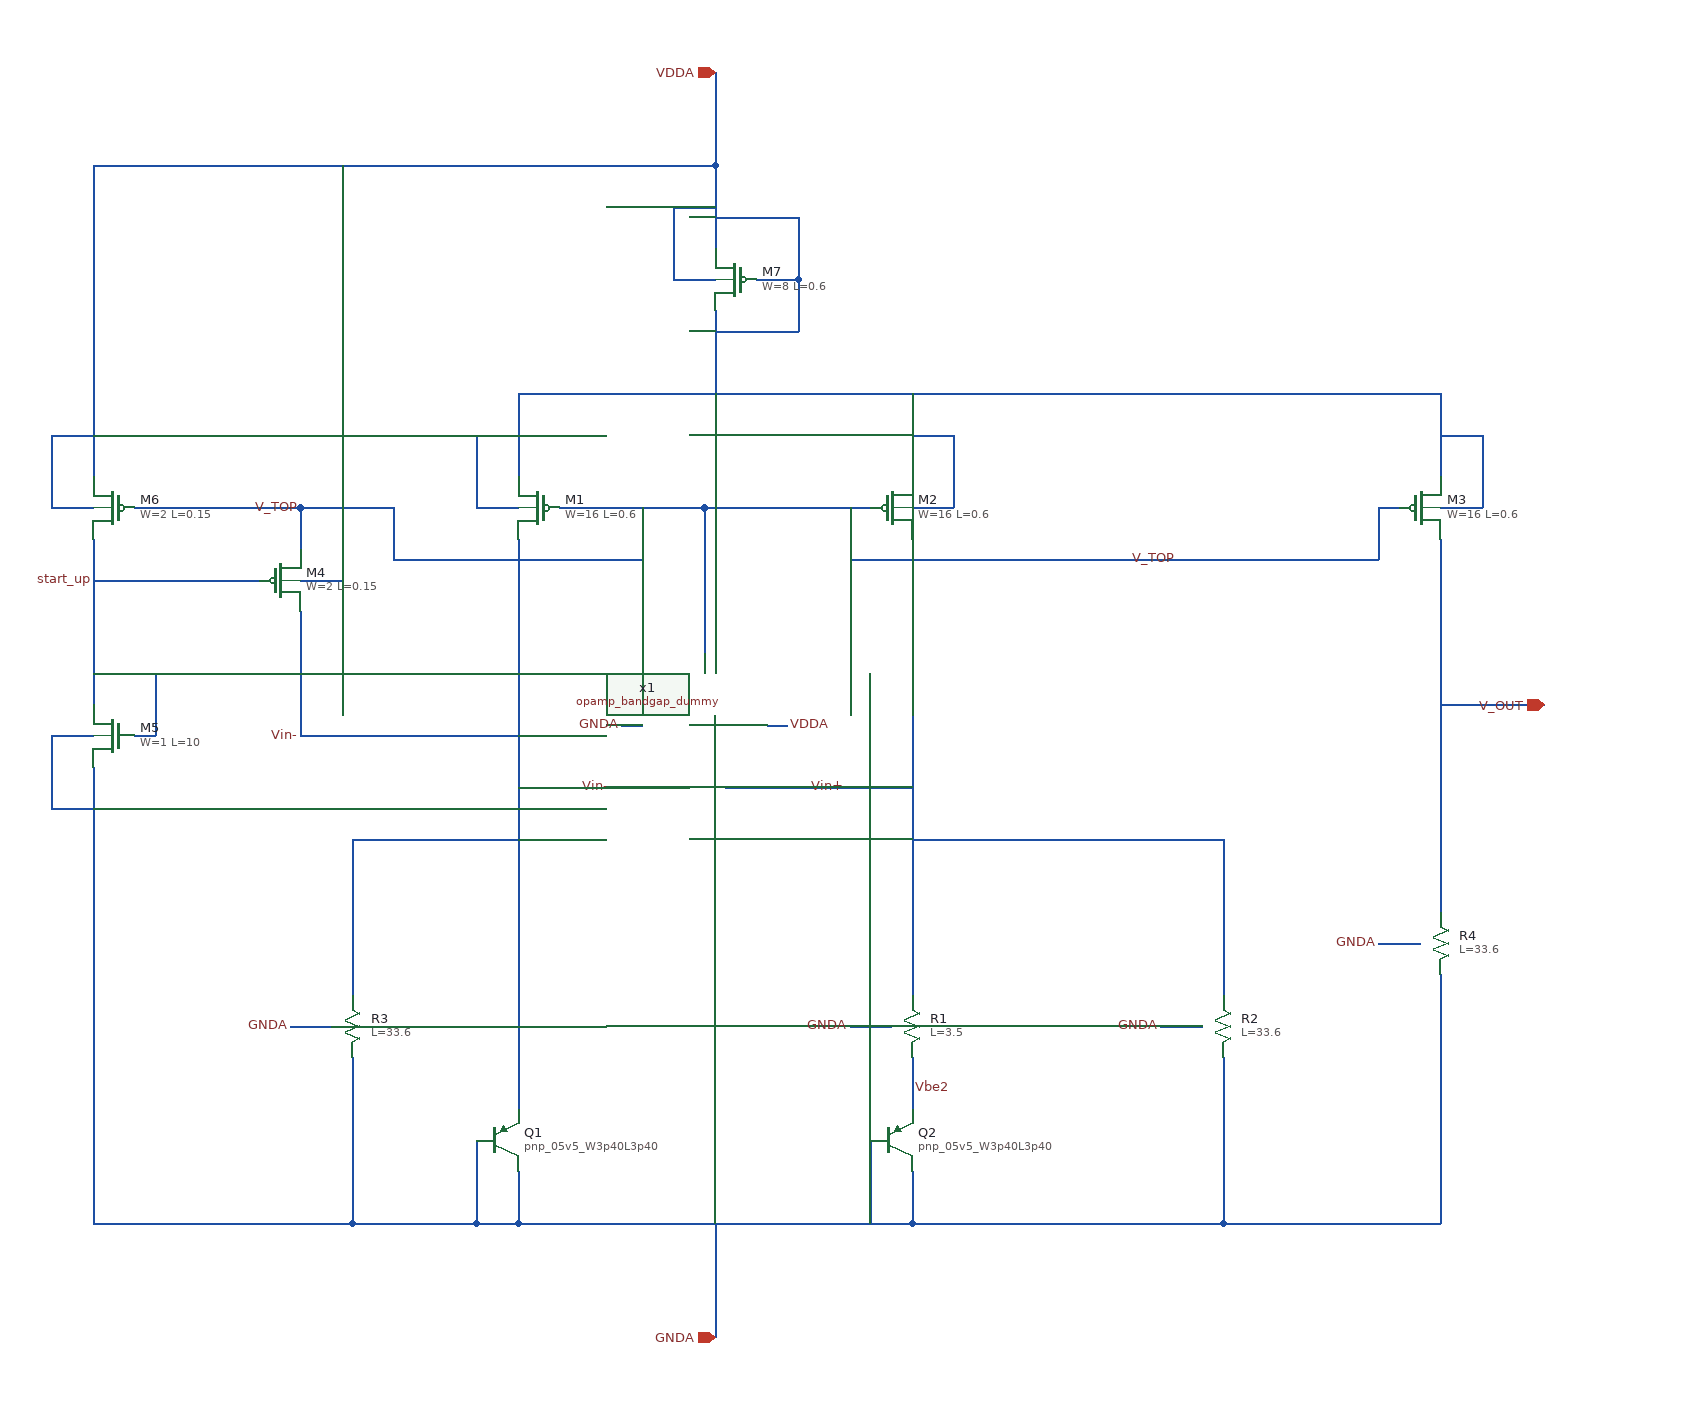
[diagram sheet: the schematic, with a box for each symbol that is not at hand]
v {xschem version=3.4.6 file_version=1.2}
G {}
K {}
V {}
S {}
E {}
N 700 -260 1080 -260 {
lab=GNDA}
N 660 -340 660 -260 {
lab=GNDA}
N 1040 -340 1040 -260 {
lab=GNDA}
N 660 -260 700 -260 {
lab=GNDA}
N 740 -950 880 -950 {
lab=V_TOP}
N 880 -950 1040 -950 {
lab=V_TOP}
N 700 -1060 700 -980 {
lab=VDDA}
N 1080 -1060 1080 -980 {
lab=VDDA}
N 540 -630 700 -630 {
lab=Vin-}
N 1080 -420 1080 -370 {lab=Vbe2}
N 1380 -420 1380 -260 {lab=GNDA}
N 540 -420 540 -260 {lab=GNDA}
N 1080 -630 1380 -630 {lab=Vin+}
N 1080 -260 1380 -260 {lab=GNDA}
N 1590 -500 1590 -260 {lab=GNDA}
N 1380 -260 1590 -260 {lab=GNDA}
N 1080 -950 1120 -950 {lab=VDDA}
N 1120 -1020 1120 -950 {lab=VDDA}
N 1080 -1020 1120 -1020 {lab=VDDA}
N 660 -950 700 -950 {lab=VDDA}
N 660 -1020 660 -950 {lab=VDDA}
N 660 -1020 700 -1020 {lab=VDDA}
N 1590 -1060 1590 -980 {
lab=VDDA}
N 1590 -950 1630 -950 {lab=VDDA}
N 1630 -1020 1630 -950 {lab=VDDA}
N 1590 -1020 1630 -1020 {lab=VDDA}
N 1020 -950 1020 -900 {lab=V_TOP}
N 1020 -900 1530 -900 {lab=V_TOP}
N 1530 -950 1530 -900 {lab=V_TOP}
N 1530 -950 1550 -950 {lab=V_TOP}
N 1590 -760 1690 -760 {lab=V_OUT}
N 900 -680 1080 -680 {lab=Vin+}
N 700 -680 860 -680 {lab=Vin-}
N 540 -260 660 -260 {lab=GNDA}
N 1080 -310 1080 -260 {lab=GNDA}
N 700 -310 700 -260 {lab=GNDA}
N 490 -950 490 -910 {lab=V_TOP}
N 290 -850 290 -760 {lab=start_up}
N 290 -1060 290 -980 {
lab=VDDA}
N 250 -950 290 -950 {lab=VDDA}
N 250 -1020 250 -950 {lab=VDDA}
N 250 -1020 290 -1020 {lab=VDDA}
N 290 -920 290 -850 {lab=start_up}
N 490 -950 580 -950 {lab=V_TOP}
N 580 -950 580 -900 {lab=V_TOP}
N 580 -900 820 -900 {lab=V_TOP}
N 290 -880 450 -880 {lab=start_up}
N 290 -260 540 -260 {lab=GNDA}
N 880 -950 880 -810 {lab=V_TOP}
N 820 -950 820 -900 {lab=V_TOP}
N 490 -730 700 -730 {lab=Vin-}
N 250 -660 290 -660 {lab=GNDA}
N 250 -730 250 -660 {lab=GNDA}
N 250 -730 290 -730 {lab=GNDA}
N 290 -700 290 -630 {lab=GNDA}
N 290 -340 290 -260 {lab=GNDA}
N 490 -880 530 -880 {lab=VDDA}
N 530 -930 530 -880 {lab=VDDA}
N 290 -630 290 -340 {lab=GNDA}
N 330 -950 490 -950 {lab=V_TOP}
N 290 -790 350 -790 {lab=start_up}
N 350 -790 350 -730 {lab=start_up}
N 330 -730 350 -730 {lab=start_up}
N 490 -850 490 -730 {lab=Vin-}
N 700 -920 700 -370 {lab=Vin-}
N 540 -630 540 -480 {lab=Vin-}
N 1080 -920 1080 -480 {lab=Vin+}
N 1380 -630 1380 -480 {lab=Vin+}
N 1590 -920 1590 -560 {lab=V_OUT}
N 890 -1370 890 -1280 {lab=VDDA}
N 890 -260 890 -150 {lab=GNDA}
N 480 -450 520 -450 {lab=GNDA}
N 1020 -450 1060 -450 {lab=GNDA}
N 1320 -450 1360 -450 {lab=GNDA}
N 1530 -530 1570 -530 {lab=GNDA}
N 800 -740 820 -740 {lab=GNDA}
N 940 -740 960 -740 {lab=VDDA}
N 890 -1280 890 -1200 {
lab=VDDA}
N 850 -1170 890 -1170 {lab=VDDA}
N 850 -1240 850 -1170 {lab=VDDA}
N 850 -1240 890 -1240 {lab=VDDA}
N 290 -1280 290 -1060 {lab=VDDA}
N 700 -1060 1590 -1060 {lab=VDDA}
N 930 -1170 970 -1170 {lab=VDDA}
N 970 -1230 970 -1170 {lab=VDDA}
N 890 -1230 970 -1230 {lab=VDDA}
N 890 -1140 890 -1060 {lab=VDDA}
N 290 -1280 890 -1280 {lab=VDDA}
N 530 -1280 530 -930 {lab=VDDA}
N 970 -1170 970 -1120 {lab=VDDA}
N 890 -1120 970 -1120 {lab=VDDA}
C {devices/lab_pin.sym} 1080 -390 2 0 {name=p5 sig_type=std_logic lab=Vbe2}
C {devices/lab_pin.sym} 960 -740 2 0 {name=p4 sig_type=std_logic lab=VDDA
}
C {sky130_fd_pr/pnp_05v5.sym} 680 -340 0 0 {name=Q1
model=pnp_05v5_W3p40L3p40
m=1
spiceprefix=X
}
C {sky130_fd_pr/pnp_05v5.sym} 1060 -340 0 0 {name=Q2
model=pnp_05v5_W3p40L3p40
m=6
spiceprefix=X
}
C {sky130_fd_pr/pfet_01v8.sym} 720 -950 0 1 {name=M1
W=16
L=0.6
nf=4
mult=1
ad="'int((nf+1)/2) * W/nf * 0.29'" 
pd="'2*int((nf+1)/2) * (W/nf + 0.29)'"
as="'int((nf+2)/2) * W/nf * 0.29'" 
ps="'2*int((nf+2)/2) * (W/nf + 0.29)'"
nrd="'0.29 / W'" nrs="'0.29 / W'"
sa=0 sb=0 sd=0
model=pfet_01v8
spiceprefix=X
}
C {sky130_fd_pr/pfet_01v8.sym} 1060 -950 0 0 {name=M2
W=16
L=0.6
nf=4
mult=1
ad="'int((nf+1)/2) * W/nf * 0.29'" 
pd="'2*int((nf+1)/2) * (W/nf + 0.29)'"
as="'int((nf+2)/2) * W/nf * 0.29'" 
ps="'2*int((nf+2)/2) * (W/nf + 0.29)'"
nrd="'0.29 / W'" nrs="'0.29 / W'"
sa=0 sb=0 sd=0
model=pfet_01v8
spiceprefix=X
}
C {sky130_fd_pr/pfet_01v8.sym} 1570 -950 0 0 {name=M3
W=16
L=0.6
nf=4
mult=1
ad="'int((nf+1)/2) * W/nf * 0.29'" 
pd="'2*int((nf+1)/2) * (W/nf + 0.29)'"
as="'int((nf+2)/2) * W/nf * 0.29'" 
ps="'2*int((nf+2)/2) * (W/nf + 0.29)'"
nrd="'0.29 / W'" nrs="'0.29 / W'"
sa=0 sb=0 sd=0
model=pfet_01v8
spiceprefix=X
}
C {lab_wire.sym} 1290 -900 2 0 {name=p2 sig_type=std_logic lab=V_TOP}
C {lab_wire.sym} 980 -680 2 0 {name=p6 sig_type=std_logic lab=Vin+}
C {lab_wire.sym} 790 -680 2 1 {name=p1 sig_type=std_logic lab=Vin-}
C {sky130_fd_pr/res_xhigh_po_0p35.sym} 1080 -450 0 0 {name=R1
L=3.5
model=res_xhigh_po_0p35
spiceprefix=X
mult=1}
C {sky130_fd_pr/res_xhigh_po_0p35.sym} 1380 -450 0 0 {name=R2
L=33.6
model=res_xhigh_po_0p35
spiceprefix=X
mult=1}
C {sky130_fd_pr/res_xhigh_po_0p35.sym} 540 -450 0 0 {name=R3
L=33.6
model=res_xhigh_po_0p35
spiceprefix=X
mult=1}
C {sky130_fd_pr/res_xhigh_po_0p35.sym} 1590 -530 0 0 {name=R4
L=33.6
model=res_xhigh_po_0p35
spiceprefix=X
mult=1}
C {opamp_bandgap_dummy.sym} 880 -740 1 1 {name=x1}
C {sky130_fd_pr/nfet_01v8.sym} 310 -730 0 1 {name=M5
W=1
L=10
nf=1 
mult=1
ad="'int((nf+1)/2) * W/nf * 0.29'" 
pd="'2*int((nf+1)/2) * (W/nf + 0.29)'"
as="'int((nf+2)/2) * W/nf * 0.29'" 
ps="'2*int((nf+2)/2) * (W/nf + 0.29)'"
nrd="'0.29 / W'" nrs="'0.29 / W'"
sa=0 sb=0 sd=0
model=nfet_01v8
spiceprefix=X
}
C {sky130_fd_pr/pfet_01v8.sym} 310 -950 0 1 {name=M6
W=2
L=0.15
nf=1
mult=1
ad="'int((nf+1)/2) * W/nf * 0.29'" 
pd="'2*int((nf+1)/2) * (W/nf + 0.29)'"
as="'int((nf+2)/2) * W/nf * 0.29'" 
ps="'2*int((nf+2)/2) * (W/nf + 0.29)'"
nrd="'0.29 / W'" nrs="'0.29 / W'"
sa=0 sb=0 sd=0
model=pfet_01v8
spiceprefix=X
}
C {devices/lab_pin.sym} 290 -880 2 1 {name=p7 sig_type=std_logic lab=start_up}
C {lab_wire.sym} 490 -730 2 1 {name=p3 sig_type=std_logic lab=Vin-}
C {lab_wire.sym} 490 -950 0 0 {name=p8 sig_type=std_logic lab=V_TOP}
C {sky130_fd_pr/pfet_01v8.sym} 470 -880 0 0 {name=M4
W=2
L=0.15
nf=1
mult=1
ad="'int((nf+1)/2) * W/nf * 0.29'" 
pd="'2*int((nf+1)/2) * (W/nf + 0.29)'"
as="'int((nf+2)/2) * W/nf * 0.29'" 
ps="'2*int((nf+2)/2) * (W/nf + 0.29)'"
nrd="'0.29 / W'" nrs="'0.29 / W'"
sa=0 sb=0 sd=0
model=pfet_01v8
spiceprefix=X
}
C {iopin.sym} 890 -1370 0 0 {name=p9 lab=VDDA}
C {iopin.sym} 890 -150 0 0 {name=p10 lab=GNDA}
C {iopin.sym} 1690 -760 0 0 {name=p11 lab=V_OUT}
C {sky130_fd_pr/pfet_01v8.sym} 910 -1170 0 1 {name=M7
W=8
L=0.6
nf=2
mult=1
ad="'int((nf+1)/2) * W/nf * 0.29'" 
pd="'2*int((nf+1)/2) * (W/nf + 0.29)'"
as="'int((nf+2)/2) * W/nf * 0.29'" 
ps="'2*int((nf+2)/2) * (W/nf + 0.29)'"
nrd="'0.29 / W'" nrs="'0.29 / W'"
sa=0 sb=0 sd=0
model=pfet_01v8
spiceprefix=X
}
C {devices/lab_pin.sym} 800 -740 2 1 {name=p12 sig_type=std_logic lab=GNDA}
C {devices/lab_pin.sym} 480 -450 2 1 {name=p13 sig_type=std_logic lab=GNDA}
C {devices/lab_pin.sym} 1020 -450 2 1 {name=p14 sig_type=std_logic lab=GNDA}
C {devices/lab_pin.sym} 1320 -450 2 1 {name=p15 sig_type=std_logic lab=GNDA}
C {devices/lab_pin.sym} 1530 -530 2 1 {name=p16 sig_type=std_logic lab=GNDA}
